VERSION 5.7 ;
  NOWIREEXTENSIONATPIN ON ;
  DIVIDERCHAR "/" ;
  BUSBITCHARS "[]" ;
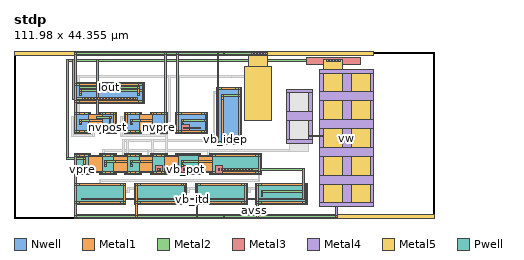
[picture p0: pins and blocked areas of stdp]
MACRO stdp
  CLASS BLOCK ;
  FOREIGN stdp ;
  ORIGIN 0.000 0.000 ;
  SIZE 111.980 BY 44.355 ;
  PIN avdd
    USE POWER ;
    PORT
      LAYER Nwell ;
        RECT 16.000 30.555 34.860 36.155 ;
        RECT 16.000 22.655 20.490 28.255 ;
        RECT 22.790 22.655 27.280 28.255 ;
        RECT 29.580 22.655 34.070 28.255 ;
        RECT 36.370 22.655 40.860 28.255 ;
        RECT 43.160 22.655 51.620 28.255 ;
        RECT 53.920 19.610 60.580 34.900 ;
      LAYER Metal1 ;
        RECT 16.230 43.605 16.730 44.105 ;
        RECT 40.170 43.605 40.670 44.105 ;
        RECT 43.390 43.605 43.890 44.105 ;
        RECT 54.150 43.605 54.650 44.105 ;
        RECT 16.230 35.945 16.690 43.605 ;
        RECT 16.230 35.445 16.730 35.945 ;
        RECT 17.580 35.445 33.280 35.945 ;
        RECT 34.130 35.445 34.630 35.945 ;
        RECT 16.230 31.265 16.690 35.445 ;
        RECT 34.170 34.250 34.630 35.445 ;
        RECT 17.400 33.750 17.900 34.250 ;
        RECT 34.130 33.750 34.630 34.250 ;
        RECT 17.420 33.200 17.880 33.750 ;
        RECT 17.400 32.700 17.900 33.200 ;
        RECT 34.170 31.265 34.630 33.750 ;
        RECT 16.230 30.765 16.730 31.265 ;
        RECT 17.580 30.765 33.280 31.265 ;
        RECT 34.130 30.765 34.630 31.265 ;
        RECT 16.230 28.045 16.690 30.765 ;
        RECT 40.170 28.045 40.630 43.605 ;
        RECT 16.230 27.545 16.730 28.045 ;
        RECT 17.595 27.545 18.895 28.045 ;
        RECT 19.760 27.615 20.260 28.045 ;
        RECT 23.020 27.615 23.520 28.045 ;
        RECT 19.760 27.545 23.520 27.615 ;
        RECT 24.385 27.545 25.685 28.045 ;
        RECT 26.550 27.545 27.050 28.045 ;
        RECT 16.230 23.365 16.690 27.545 ;
        RECT 19.800 26.350 23.480 27.545 ;
        RECT 17.400 25.850 17.900 26.350 ;
        RECT 19.760 25.850 23.480 26.350 ;
        RECT 17.420 25.300 17.880 25.850 ;
        RECT 17.400 24.800 17.900 25.300 ;
        RECT 19.800 23.365 23.480 25.850 ;
        RECT 26.590 23.365 27.050 27.545 ;
        RECT 16.230 22.865 16.730 23.365 ;
        RECT 17.595 22.865 18.895 23.365 ;
        RECT 19.760 23.295 23.520 23.365 ;
        RECT 19.760 22.865 20.260 23.295 ;
        RECT 23.020 22.865 23.520 23.295 ;
        RECT 24.385 22.865 25.685 23.365 ;
        RECT 26.550 22.865 27.050 23.365 ;
        RECT 29.810 27.545 30.310 28.045 ;
        RECT 31.175 27.545 32.475 28.045 ;
        RECT 33.340 27.615 33.840 28.045 ;
        RECT 36.600 27.615 37.100 28.045 ;
        RECT 33.340 27.545 37.100 27.615 ;
        RECT 37.965 27.545 39.265 28.045 ;
        RECT 40.130 27.545 40.630 28.045 ;
        RECT 29.810 23.365 30.270 27.545 ;
        RECT 33.380 26.350 37.060 27.545 ;
        RECT 30.980 25.850 31.480 26.350 ;
        RECT 33.340 25.850 37.060 26.350 ;
        RECT 31.000 25.300 31.460 25.850 ;
        RECT 30.980 24.800 31.480 25.300 ;
        RECT 33.380 23.365 37.060 25.850 ;
        RECT 40.170 23.365 40.630 27.545 ;
        RECT 29.810 22.865 30.310 23.365 ;
        RECT 31.175 22.865 32.475 23.365 ;
        RECT 33.340 23.295 37.100 23.365 ;
        RECT 33.340 22.865 33.840 23.295 ;
        RECT 36.600 22.865 37.100 23.295 ;
        RECT 37.965 22.865 39.265 23.365 ;
        RECT 40.130 22.865 40.630 23.365 ;
        RECT 43.390 28.045 43.850 43.605 ;
        RECT 54.150 34.690 54.610 43.605 ;
        RECT 54.150 34.190 54.650 34.690 ;
        RECT 55.400 34.190 59.100 34.690 ;
        RECT 59.850 34.190 60.350 34.690 ;
        RECT 43.390 27.545 43.890 28.045 ;
        RECT 44.740 27.545 50.040 28.045 ;
        RECT 50.890 27.545 51.390 28.045 ;
        RECT 43.390 23.365 43.850 27.545 ;
        RECT 50.930 26.350 51.390 27.545 ;
        RECT 44.560 25.850 45.060 26.350 ;
        RECT 50.890 25.850 51.390 26.350 ;
        RECT 44.580 25.300 45.040 25.850 ;
        RECT 44.560 24.800 45.060 25.300 ;
        RECT 50.930 23.365 51.390 25.850 ;
        RECT 43.390 22.865 43.890 23.365 ;
        RECT 44.740 22.865 50.040 23.365 ;
        RECT 50.890 22.865 51.390 23.365 ;
        RECT 54.150 20.320 54.610 34.190 ;
        RECT 59.890 33.000 60.350 34.190 ;
        RECT 55.320 32.500 55.820 33.000 ;
        RECT 59.850 32.500 60.350 33.000 ;
        RECT 55.340 31.500 55.800 32.500 ;
        RECT 55.320 22.200 55.820 31.500 ;
        RECT 55.340 21.750 55.800 22.200 ;
        RECT 59.890 20.320 60.350 32.500 ;
        RECT 54.150 19.820 54.650 20.320 ;
        RECT 55.400 19.820 59.100 20.320 ;
        RECT 59.850 19.820 60.350 20.320 ;
      LAYER Metal2 ;
        RECT 16.230 43.605 67.580 44.105 ;
        RECT 16.230 35.445 34.630 35.945 ;
        RECT 17.400 33.750 34.630 34.250 ;
        RECT 54.150 34.190 60.350 34.690 ;
        RECT 17.400 32.700 17.900 33.200 ;
        RECT 55.320 32.500 60.350 33.000 ;
        RECT 16.230 30.765 34.630 31.265 ;
        RECT 16.230 27.545 20.260 28.045 ;
        RECT 23.020 27.545 27.050 28.045 ;
        RECT 29.810 27.545 33.840 28.045 ;
        RECT 36.600 27.545 40.630 28.045 ;
        RECT 43.390 27.545 51.390 28.045 ;
        RECT 17.400 25.850 20.260 26.350 ;
        RECT 30.980 25.850 33.840 26.350 ;
        RECT 44.560 25.850 51.390 26.350 ;
        RECT 17.400 24.800 17.900 25.300 ;
        RECT 30.980 24.800 31.480 25.300 ;
        RECT 44.560 24.800 45.060 25.300 ;
        RECT 16.230 22.865 20.260 23.365 ;
        RECT 23.020 22.865 27.050 23.365 ;
        RECT 29.810 22.865 33.840 23.365 ;
        RECT 36.600 22.865 40.630 23.365 ;
        RECT 43.390 22.865 51.390 23.365 ;
        RECT 55.320 21.750 55.820 31.950 ;
        RECT 54.150 19.820 60.350 20.320 ;
      LAYER Metal3 ;
        RECT 55.740 43.605 56.240 44.105 ;
        RECT 63.230 43.605 63.730 44.105 ;
        RECT 64.030 43.605 64.530 44.105 ;
        RECT 64.830 43.605 65.330 44.105 ;
        RECT 65.630 43.605 66.130 44.105 ;
        RECT 66.430 43.605 66.930 44.105 ;
      LAYER Metal4 ;
        RECT 55.740 43.605 56.240 44.105 ;
        RECT 63.230 43.605 63.730 44.105 ;
        RECT 64.030 43.605 64.530 44.105 ;
        RECT 64.830 43.605 65.330 44.105 ;
        RECT 65.630 43.605 66.130 44.105 ;
        RECT 66.430 43.605 66.930 44.105 ;
      LAYER Metal5 ;
        RECT 0.000 43.355 95.980 44.355 ;
        RECT 62.580 40.355 67.580 43.355 ;
        RECT 61.580 25.955 68.580 40.355 ;
    END
  END avdd
  PIN avss
    USE GROUND ;
    PORT
      LAYER Pwell ;
        RECT 16.000 11.600 20.490 17.200 ;
        RECT 22.790 11.600 27.280 17.200 ;
        RECT 29.580 11.600 34.070 17.200 ;
        RECT 36.370 11.600 40.860 17.200 ;
        RECT 43.160 11.545 49.820 17.255 ;
        RECT 52.120 11.600 65.980 17.200 ;
        RECT 16.000 3.700 29.860 9.300 ;
        RECT 32.160 3.700 46.020 9.300 ;
        RECT 48.320 3.700 62.180 9.300 ;
        RECT 64.480 3.700 78.340 9.300 ;
      LAYER Metal1 ;
        RECT 16.230 16.490 16.730 16.990 ;
        RECT 17.595 16.490 18.895 16.990 ;
        RECT 19.760 16.560 20.260 16.990 ;
        RECT 23.020 16.560 23.520 16.990 ;
        RECT 19.760 16.490 23.520 16.560 ;
        RECT 24.385 16.490 25.685 16.990 ;
        RECT 26.550 16.560 27.050 16.990 ;
        RECT 29.810 16.560 30.310 16.990 ;
        RECT 26.550 16.490 30.310 16.560 ;
        RECT 31.175 16.490 32.475 16.990 ;
        RECT 33.340 16.560 33.840 16.990 ;
        RECT 36.600 16.560 37.100 16.990 ;
        RECT 33.340 16.490 37.100 16.560 ;
        RECT 37.965 16.490 39.265 16.990 ;
        RECT 40.130 16.560 40.630 16.990 ;
        RECT 43.390 16.560 43.890 17.045 ;
        RECT 40.130 16.545 43.890 16.560 ;
        RECT 44.640 16.545 48.340 17.045 ;
        RECT 49.090 16.615 49.590 17.045 ;
        RECT 52.350 16.615 52.850 16.990 ;
        RECT 49.090 16.545 52.850 16.615 ;
        RECT 40.130 16.490 43.850 16.545 ;
        RECT 16.230 12.310 16.690 16.490 ;
        RECT 19.800 12.310 23.480 16.490 ;
        RECT 26.590 15.295 30.270 16.490 ;
        RECT 33.380 15.295 37.060 16.490 ;
        RECT 24.190 14.795 24.690 15.295 ;
        RECT 26.550 14.795 30.270 15.295 ;
        RECT 30.980 14.795 31.480 15.295 ;
        RECT 33.340 14.795 37.060 15.295 ;
        RECT 24.210 14.245 24.670 14.795 ;
        RECT 24.190 13.745 24.690 14.245 ;
        RECT 26.590 12.310 30.270 14.795 ;
        RECT 31.000 14.245 31.460 14.795 ;
        RECT 30.980 13.745 31.480 14.245 ;
        RECT 33.380 12.310 37.060 14.795 ;
        RECT 40.170 12.310 43.850 16.490 ;
        RECT 49.130 16.490 52.850 16.545 ;
        RECT 53.600 16.490 64.500 16.990 ;
        RECT 65.250 16.490 65.750 16.990 ;
        RECT 49.130 15.355 52.810 16.490 ;
        RECT 44.560 14.855 45.060 15.355 ;
        RECT 49.090 14.855 52.810 15.355 ;
        RECT 44.580 14.250 45.040 14.855 ;
        RECT 44.560 13.750 45.060 14.250 ;
        RECT 44.580 13.695 45.040 13.750 ;
        RECT 16.230 11.810 16.730 12.310 ;
        RECT 17.595 11.810 18.895 12.310 ;
        RECT 19.760 12.240 23.520 12.310 ;
        RECT 19.760 11.810 20.260 12.240 ;
        RECT 23.020 11.810 23.520 12.240 ;
        RECT 24.385 11.810 25.685 12.310 ;
        RECT 26.550 12.240 30.310 12.310 ;
        RECT 26.550 11.810 27.050 12.240 ;
        RECT 29.810 11.810 30.310 12.240 ;
        RECT 31.175 11.810 32.475 12.310 ;
        RECT 33.340 12.240 37.100 12.310 ;
        RECT 33.340 11.810 33.840 12.240 ;
        RECT 36.600 11.810 37.100 12.240 ;
        RECT 37.965 11.810 39.265 12.310 ;
        RECT 40.130 12.255 43.850 12.310 ;
        RECT 49.130 12.310 52.810 14.855 ;
        RECT 65.290 12.310 65.750 16.490 ;
        RECT 49.130 12.255 52.850 12.310 ;
        RECT 40.130 12.240 43.890 12.255 ;
        RECT 40.130 11.810 40.630 12.240 ;
        RECT 16.230 9.090 16.690 11.810 ;
        RECT 43.390 11.755 43.890 12.240 ;
        RECT 44.640 11.755 48.340 12.255 ;
        RECT 49.090 12.185 52.850 12.255 ;
        RECT 49.090 11.755 49.590 12.185 ;
        RECT 52.350 11.810 52.850 12.185 ;
        RECT 53.600 11.810 64.500 12.310 ;
        RECT 65.250 11.810 65.750 12.310 ;
        RECT 16.230 8.590 16.730 9.090 ;
        RECT 17.480 8.590 28.380 9.090 ;
        RECT 29.130 8.590 29.630 9.090 ;
        RECT 16.230 4.410 16.690 8.590 ;
        RECT 29.170 4.410 29.630 8.590 ;
        RECT 16.230 3.910 16.730 4.410 ;
        RECT 17.480 3.910 28.380 4.410 ;
        RECT 29.130 3.910 29.630 4.410 ;
        RECT 32.390 8.590 32.890 9.090 ;
        RECT 33.640 8.590 44.540 9.090 ;
        RECT 45.290 8.590 45.790 9.090 ;
        RECT 32.390 4.410 32.850 8.590 ;
        RECT 45.330 4.410 45.790 8.590 ;
        RECT 32.390 3.910 32.890 4.410 ;
        RECT 33.640 3.910 44.540 4.410 ;
        RECT 45.290 3.910 45.790 4.410 ;
        RECT 48.550 8.590 49.050 9.090 ;
        RECT 49.800 8.590 60.700 9.090 ;
        RECT 61.450 8.590 61.950 9.090 ;
        RECT 48.550 4.410 49.010 8.590 ;
        RECT 61.490 4.410 61.950 8.590 ;
        RECT 48.550 3.910 49.050 4.410 ;
        RECT 49.800 3.910 60.700 4.410 ;
        RECT 61.450 3.910 61.950 4.410 ;
        RECT 64.710 8.590 65.210 9.090 ;
        RECT 65.960 8.590 76.860 9.090 ;
        RECT 77.610 8.590 78.110 9.090 ;
        RECT 64.710 4.410 65.170 8.590 ;
        RECT 77.650 7.395 78.110 8.590 ;
        RECT 65.880 6.895 66.380 7.395 ;
        RECT 77.610 6.895 78.110 7.395 ;
        RECT 65.900 6.345 66.360 6.895 ;
        RECT 65.880 5.845 66.380 6.345 ;
        RECT 77.650 4.410 78.110 6.895 ;
        RECT 64.710 3.910 65.210 4.410 ;
        RECT 65.960 3.910 76.860 4.410 ;
        RECT 77.610 3.910 78.110 4.410 ;
        RECT 16.230 0.750 16.690 3.910 ;
        RECT 32.390 0.750 32.850 3.910 ;
        RECT 48.550 0.750 49.010 3.910 ;
        RECT 64.710 0.750 65.170 3.910 ;
        RECT 16.230 0.250 16.730 0.750 ;
        RECT 32.390 0.250 32.890 0.750 ;
        RECT 48.550 0.250 49.050 0.750 ;
        RECT 64.670 0.250 65.170 0.750 ;
      LAYER Metal2 ;
        RECT 16.230 16.490 20.260 16.990 ;
        RECT 23.020 16.490 27.050 16.990 ;
        RECT 29.810 16.490 33.840 16.990 ;
        RECT 36.600 16.490 40.630 16.990 ;
        RECT 43.390 16.545 49.590 17.045 ;
        RECT 52.350 16.490 65.750 16.990 ;
        RECT 24.190 14.795 27.050 15.295 ;
        RECT 30.980 14.795 33.840 15.295 ;
        RECT 44.560 14.855 49.590 15.355 ;
        RECT 24.190 13.745 24.690 14.245 ;
        RECT 30.980 13.745 31.480 14.245 ;
        RECT 44.560 13.695 45.060 14.305 ;
        RECT 16.230 11.810 20.260 12.310 ;
        RECT 23.020 11.810 27.050 12.310 ;
        RECT 29.810 11.810 33.840 12.310 ;
        RECT 36.600 11.810 40.630 12.310 ;
        RECT 43.390 11.755 49.590 12.255 ;
        RECT 52.350 11.810 65.750 12.310 ;
        RECT 16.230 8.590 29.630 9.090 ;
        RECT 32.390 8.590 45.790 9.090 ;
        RECT 48.550 8.590 61.950 9.090 ;
        RECT 64.710 8.590 78.110 9.090 ;
        RECT 65.880 6.895 78.110 7.395 ;
        RECT 65.880 5.845 66.380 6.345 ;
        RECT 16.230 3.910 29.630 4.410 ;
        RECT 32.390 3.910 45.790 4.410 ;
        RECT 48.550 3.910 61.950 4.410 ;
        RECT 64.710 3.910 78.110 4.410 ;
        RECT 16.230 0.250 86.130 0.750 ;
      LAYER Metal3 ;
        RECT 55.740 0.250 56.240 0.750 ;
        RECT 85.630 0.250 86.130 0.750 ;
      LAYER Metal4 ;
        RECT 81.580 38.600 95.980 39.600 ;
        RECT 72.580 33.355 79.580 34.355 ;
        RECT 72.580 28.355 73.580 33.355 ;
        RECT 78.580 28.355 79.580 33.355 ;
        RECT 72.580 25.955 79.580 28.355 ;
        RECT 72.580 20.955 73.580 25.955 ;
        RECT 78.580 22.105 79.580 25.955 ;
        RECT 81.580 33.600 82.580 38.600 ;
        RECT 87.580 33.600 89.980 38.600 ;
        RECT 94.980 33.600 95.980 38.600 ;
        RECT 81.580 31.200 95.980 33.600 ;
        RECT 81.580 26.200 82.580 31.200 ;
        RECT 87.580 26.200 89.980 31.200 ;
        RECT 94.980 26.200 95.980 31.200 ;
        RECT 81.580 23.800 95.980 26.200 ;
        RECT 81.580 22.105 82.580 23.800 ;
        RECT 78.580 21.605 82.580 22.105 ;
        RECT 78.580 20.955 79.580 21.605 ;
        RECT 72.580 19.955 79.580 20.955 ;
        RECT 81.580 18.800 82.580 21.605 ;
        RECT 87.580 18.800 89.980 23.800 ;
        RECT 94.980 18.800 95.980 23.800 ;
        RECT 81.580 16.400 95.980 18.800 ;
        RECT 81.580 11.400 82.580 16.400 ;
        RECT 87.580 11.400 89.980 16.400 ;
        RECT 94.980 11.400 95.980 16.400 ;
        RECT 81.580 9.000 95.980 11.400 ;
        RECT 81.580 4.000 82.580 9.000 ;
        RECT 87.580 4.000 89.980 9.000 ;
        RECT 94.980 4.000 95.980 9.000 ;
        RECT 81.580 3.000 95.980 4.000 ;
        RECT 55.740 0.250 56.240 0.750 ;
        RECT 85.630 0.250 86.130 3.000 ;
      LAYER Metal5 ;
        RECT 16.000 0.000 111.980 1.000 ;
    END
  END avss
  PIN nvpost
    ANTENNAGATEAREA 0.315000 ;
    PORT
      LAYER Metal1 ;
        RECT 24.785 23.760 25.285 24.260 ;
      LAYER Metal2 ;
        RECT 24.720 23.760 25.350 24.260 ;
      LAYER Metal3 ;
        RECT 24.035 23.010 26.035 25.010 ;
    END
  END nvpost
  PIN vpost
    ANTENNAGATEAREA 0.315000 ;
    PORT
      LAYER Metal1 ;
        RECT 38.365 12.705 38.865 13.205 ;
      LAYER Metal2 ;
        RECT 38.300 12.705 38.930 13.205 ;
      LAYER Metal3 ;
        RECT 37.615 11.955 39.615 13.955 ;
    END
  END vpost
  PIN vpre
    ANTENNAGATEAREA 0.315000 ;
    PORT
      LAYER Metal1 ;
        RECT 17.995 12.705 18.495 13.205 ;
      LAYER Metal2 ;
        RECT 17.930 12.705 18.560 13.205 ;
      LAYER Metal3 ;
        RECT 17.245 11.955 19.245 13.955 ;
    END
  END vpre
  PIN vb_idep
    ANTENNAGATEAREA 28.559999 ;
    PORT
      LAYER Metal1 ;
        RECT 56.200 20.710 56.700 21.210 ;
        RECT 57.000 20.710 57.500 21.210 ;
        RECT 57.800 20.710 58.300 21.210 ;
      LAYER Metal2 ;
        RECT 55.850 20.710 58.650 21.210 ;
      LAYER Metal3 ;
        RECT 55.450 19.960 57.450 21.960 ;
    END
  END vb_idep
  PIN vb_itd
    ANTENNAGATEAREA 25.000000 ;
    PORT
      LAYER Metal1 ;
        RECT 54.400 12.705 54.900 13.205 ;
        RECT 55.200 12.705 55.700 13.205 ;
        RECT 56.000 12.705 56.500 13.205 ;
        RECT 56.800 12.705 57.300 13.205 ;
        RECT 57.600 12.705 58.100 13.205 ;
        RECT 58.400 12.705 58.900 13.205 ;
        RECT 59.200 12.705 59.700 13.205 ;
        RECT 60.000 12.705 60.500 13.205 ;
        RECT 60.800 12.705 61.300 13.205 ;
        RECT 61.600 12.705 62.100 13.205 ;
        RECT 62.400 12.705 62.900 13.205 ;
        RECT 63.200 12.705 63.700 13.205 ;
        RECT 18.280 4.805 18.780 5.305 ;
        RECT 19.080 4.805 19.580 5.305 ;
        RECT 19.880 4.805 20.380 5.305 ;
        RECT 20.680 4.805 21.180 5.305 ;
        RECT 21.480 4.805 21.980 5.305 ;
        RECT 22.280 4.805 22.780 5.305 ;
        RECT 23.080 4.805 23.580 5.305 ;
        RECT 23.880 4.805 24.380 5.305 ;
        RECT 24.680 4.805 25.180 5.305 ;
        RECT 25.480 4.805 25.980 5.305 ;
        RECT 26.280 4.805 26.780 5.305 ;
        RECT 27.080 4.805 27.580 5.305 ;
        RECT 34.440 4.805 34.940 5.305 ;
        RECT 35.240 4.805 35.740 5.305 ;
        RECT 36.040 4.805 36.540 5.305 ;
        RECT 36.840 4.805 37.340 5.305 ;
        RECT 37.640 4.805 38.140 5.305 ;
        RECT 38.440 4.805 38.940 5.305 ;
        RECT 39.240 4.805 39.740 5.305 ;
        RECT 40.040 4.805 40.540 5.305 ;
        RECT 40.840 4.805 41.340 5.305 ;
        RECT 41.640 4.805 42.140 5.305 ;
        RECT 42.440 4.805 42.940 5.305 ;
        RECT 43.240 4.805 43.740 5.305 ;
        RECT 50.600 4.805 51.100 5.305 ;
        RECT 51.400 4.805 51.900 5.305 ;
        RECT 52.200 4.805 52.700 5.305 ;
        RECT 53.000 4.805 53.500 5.305 ;
        RECT 53.800 4.805 54.300 5.305 ;
        RECT 54.600 4.805 55.100 5.305 ;
        RECT 55.400 4.805 55.900 5.305 ;
        RECT 56.200 4.805 56.700 5.305 ;
        RECT 57.000 4.805 57.500 5.305 ;
        RECT 57.800 4.805 58.300 5.305 ;
        RECT 58.600 4.805 59.100 5.305 ;
        RECT 59.400 4.805 59.900 5.305 ;
        RECT 66.760 4.805 67.260 5.305 ;
        RECT 67.560 4.805 68.060 5.305 ;
        RECT 68.360 4.805 68.860 5.305 ;
        RECT 69.160 4.805 69.660 5.305 ;
        RECT 69.960 4.805 70.460 5.305 ;
        RECT 70.760 4.805 71.260 5.305 ;
        RECT 71.560 4.805 72.060 5.305 ;
        RECT 72.360 4.805 72.860 5.305 ;
        RECT 73.160 4.805 73.660 5.305 ;
        RECT 73.960 4.805 74.460 5.305 ;
        RECT 74.760 4.805 75.260 5.305 ;
        RECT 75.560 4.805 76.060 5.305 ;
      LAYER Metal2 ;
        RECT 54.050 12.705 77.410 13.205 ;
        RECT 17.930 4.805 77.410 5.305 ;
      LAYER Metal3 ;
        RECT 53.650 11.955 55.650 13.955 ;
        RECT 76.910 4.805 77.410 13.205 ;
    END
  END vb_itd
  PIN vb_itp
    ANTENNAGATEAREA 2.300000 ;
    PORT
      LAYER Metal1 ;
        RECT 45.540 23.760 46.040 24.260 ;
        RECT 46.340 23.760 46.840 24.260 ;
        RECT 47.140 23.760 47.640 24.260 ;
        RECT 47.940 23.760 48.440 24.260 ;
        RECT 48.740 23.760 49.240 24.260 ;
      LAYER Metal2 ;
        RECT 45.090 23.760 49.690 24.260 ;
      LAYER Metal3 ;
        RECT 44.790 23.010 46.790 25.010 ;
    END
  END vb_itp
  PIN vb_pot
    ANTENNAGATEAREA 1.708000 ;
    PORT
      LAYER Metal1 ;
        RECT 45.440 12.650 45.940 13.150 ;
        RECT 46.240 12.650 46.740 13.150 ;
        RECT 47.040 12.650 47.540 13.150 ;
      LAYER Metal2 ;
        RECT 45.090 12.650 47.890 13.150 ;
      LAYER Metal3 ;
        RECT 44.690 11.900 46.690 13.900 ;
    END
  END vb_pot
  PIN nvpre
    ANTENNAGATEAREA 0.315000 ;
    PORT
      LAYER Metal1 ;
        RECT 38.365 23.760 38.865 24.260 ;
      LAYER Metal2 ;
        RECT 38.300 23.760 38.930 24.260 ;
      LAYER Metal3 ;
        RECT 37.615 23.010 39.615 25.010 ;
      LAYER Metal4 ;
        RECT 38.365 23.760 38.865 24.260 ;
    END
  END nvpre
  PIN Iout
    ANTENNADIFFAREA 0.300000 ;
    PORT
      LAYER Metal1 ;
        RECT 32.960 34.550 33.460 35.050 ;
        RECT 32.980 33.200 33.440 34.550 ;
        RECT 32.960 32.700 33.460 33.200 ;
      LAYER Metal2 ;
        RECT 17.400 34.550 33.460 35.050 ;
        RECT 32.960 32.700 33.460 33.200 ;
      LAYER Metal3 ;
        RECT 24.430 33.800 26.430 35.800 ;
    END
  END Iout
  PIN vw
    ANTENNAGATEAREA 7.500000 ;
    ANTENNADIFFAREA 0.600000 ;
    PORT
      LAYER Metal1 ;
        RECT 18.380 31.660 18.880 32.160 ;
        RECT 19.180 31.660 19.680 32.160 ;
        RECT 19.980 31.660 20.480 32.160 ;
        RECT 20.780 31.660 21.280 32.160 ;
        RECT 21.580 31.660 22.080 32.160 ;
        RECT 22.380 31.660 22.880 32.160 ;
        RECT 23.180 31.660 23.680 32.160 ;
        RECT 23.980 31.660 24.480 32.160 ;
        RECT 24.780 31.660 25.280 32.160 ;
        RECT 25.580 31.660 26.080 32.160 ;
        RECT 26.380 31.660 26.880 32.160 ;
        RECT 27.180 31.660 27.680 32.160 ;
        RECT 27.980 31.660 28.480 32.160 ;
        RECT 28.780 31.660 29.280 32.160 ;
        RECT 29.580 31.660 30.080 32.160 ;
        RECT 30.380 31.660 30.880 32.160 ;
        RECT 31.180 31.660 31.680 32.160 ;
        RECT 31.980 31.660 32.480 32.160 ;
        RECT 25.380 26.650 25.880 27.150 ;
        RECT 25.400 25.300 25.860 26.650 ;
        RECT 25.380 24.800 25.880 25.300 ;
        RECT 18.590 15.595 19.090 16.095 ;
        RECT 18.610 14.245 19.070 15.595 ;
        RECT 18.590 13.745 19.090 14.245 ;
      LAYER Metal2 ;
        RECT 13.900 41.650 87.580 42.150 ;
        RECT 15.630 31.660 32.930 32.160 ;
        RECT 21.940 26.650 25.880 27.150 ;
        RECT 25.380 24.800 25.880 25.300 ;
        RECT 13.900 15.595 19.090 16.095 ;
        RECT 18.590 13.745 19.090 14.245 ;
      LAYER Metal3 ;
        RECT 13.900 15.595 14.400 42.150 ;
        RECT 15.630 31.660 16.130 42.150 ;
        RECT 21.940 26.650 22.440 42.150 ;
        RECT 77.880 40.900 92.280 42.900 ;
      LAYER Metal4 ;
        RECT 83.230 41.650 83.730 42.150 ;
        RECT 84.030 41.650 84.530 42.150 ;
        RECT 84.830 41.650 85.330 42.150 ;
        RECT 85.630 41.650 86.130 42.150 ;
        RECT 86.430 41.650 86.930 42.150 ;
      LAYER Metal5 ;
        RECT 82.580 39.600 87.580 42.150 ;
        RECT 81.580 3.000 95.980 39.600 ;
    END
  END vw
  OBS
      LAYER Metal1 ;
        RECT 58.680 33.300 59.180 33.800 ;
        RECT 58.700 31.500 59.160 33.300 ;
        RECT 18.590 26.650 19.090 27.150 ;
        RECT 32.170 26.650 32.670 27.150 ;
        RECT 38.960 26.650 39.460 27.150 ;
        RECT 49.720 26.650 50.220 27.150 ;
        RECT 18.610 25.300 19.070 26.650 ;
        RECT 24.190 25.850 24.690 26.350 ;
        RECT 24.210 25.300 24.670 25.850 ;
        RECT 32.190 25.300 32.650 26.650 ;
        RECT 37.770 25.850 38.270 26.350 ;
        RECT 37.790 25.300 38.250 25.850 ;
        RECT 38.980 25.300 39.440 26.650 ;
        RECT 49.740 25.300 50.200 26.650 ;
        RECT 18.590 24.800 19.090 25.300 ;
        RECT 24.190 24.800 24.690 25.300 ;
        RECT 32.170 24.800 32.670 25.300 ;
        RECT 37.770 24.800 38.270 25.300 ;
        RECT 38.960 24.800 39.460 25.300 ;
        RECT 49.720 24.800 50.220 25.300 ;
        RECT 17.995 23.760 18.495 24.260 ;
        RECT 31.575 23.760 32.075 24.260 ;
        RECT 58.680 22.200 59.180 31.500 ;
        RECT 58.700 21.750 59.160 22.200 ;
        RECT 25.380 15.595 25.880 16.095 ;
        RECT 32.170 15.595 32.670 16.095 ;
        RECT 38.960 15.595 39.460 16.095 ;
        RECT 47.920 15.655 48.420 16.155 ;
        RECT 17.400 14.795 17.900 15.295 ;
        RECT 17.420 14.245 17.880 14.795 ;
        RECT 25.400 14.245 25.860 15.595 ;
        RECT 32.190 14.245 32.650 15.595 ;
        RECT 37.770 14.795 38.270 15.295 ;
        RECT 37.790 14.245 38.250 14.795 ;
        RECT 38.980 14.245 39.440 15.595 ;
        RECT 47.940 14.250 48.400 15.655 ;
        RECT 64.080 15.595 64.580 16.095 ;
        RECT 53.520 14.795 54.020 15.295 ;
        RECT 17.400 13.745 17.900 14.245 ;
        RECT 25.380 13.745 25.880 14.245 ;
        RECT 32.170 13.745 32.670 14.245 ;
        RECT 37.770 13.745 38.270 14.245 ;
        RECT 38.960 13.745 39.460 14.245 ;
        RECT 47.920 13.750 48.420 14.250 ;
        RECT 53.540 14.245 54.000 14.795 ;
        RECT 64.100 14.245 64.560 15.595 ;
        RECT 47.940 13.695 48.400 13.750 ;
        RECT 53.520 13.745 54.020 14.245 ;
        RECT 64.080 13.745 64.580 14.245 ;
        RECT 24.785 12.705 25.285 13.205 ;
        RECT 31.575 12.705 32.075 13.205 ;
        RECT 27.960 7.695 28.460 8.195 ;
        RECT 44.120 7.695 44.620 8.195 ;
        RECT 60.280 7.695 60.780 8.195 ;
        RECT 76.440 7.695 76.940 8.195 ;
        RECT 17.400 6.895 17.900 7.395 ;
        RECT 17.420 6.345 17.880 6.895 ;
        RECT 27.980 6.345 28.440 7.695 ;
        RECT 33.560 6.895 34.060 7.395 ;
        RECT 33.580 6.345 34.040 6.895 ;
        RECT 44.140 6.345 44.600 7.695 ;
        RECT 49.720 6.895 50.220 7.395 ;
        RECT 49.740 6.345 50.200 6.895 ;
        RECT 60.300 6.345 60.760 7.695 ;
        RECT 76.460 6.345 76.920 7.695 ;
        RECT 17.400 5.845 17.900 6.345 ;
        RECT 27.960 5.845 28.460 6.345 ;
        RECT 33.560 5.845 34.060 6.345 ;
        RECT 44.120 5.845 44.620 6.345 ;
        RECT 49.720 5.845 50.220 6.345 ;
        RECT 60.280 5.845 60.780 6.345 ;
        RECT 76.440 5.845 76.940 6.345 ;
      LAYER Metal2 ;
        RECT 16.930 37.405 58.480 37.905 ;
        RECT 53.070 33.300 59.180 33.800 ;
        RECT 15.400 26.650 19.090 27.150 ;
        RECT 28.480 26.650 32.670 27.150 ;
        RECT 34.690 26.650 39.460 27.150 ;
        RECT 43.560 26.650 50.220 27.150 ;
        RECT 20.840 25.850 25.880 26.350 ;
        RECT 37.770 25.850 41.710 26.350 ;
        RECT 18.590 24.800 19.090 25.300 ;
        RECT 24.190 24.800 24.690 25.300 ;
        RECT 32.170 24.800 32.670 25.300 ;
        RECT 37.770 24.800 38.270 25.300 ;
        RECT 38.960 24.800 39.460 25.300 ;
        RECT 49.720 24.800 50.220 25.300 ;
        RECT 16.930 23.760 18.560 24.260 ;
        RECT 31.510 23.760 35.190 24.260 ;
        RECT 15.400 21.650 21.340 22.150 ;
        RECT 28.480 21.650 40.920 22.150 ;
        RECT 58.680 21.750 59.180 31.950 ;
        RECT 29.010 20.300 53.570 20.800 ;
        RECT 23.720 17.645 78.580 18.145 ;
        RECT 20.840 15.595 25.880 16.095 ;
        RECT 29.980 15.595 32.670 16.095 ;
        RECT 36.770 15.595 39.460 16.095 ;
        RECT 40.420 15.655 48.420 16.155 ;
        RECT 51.520 15.595 64.580 16.095 ;
        RECT 17.400 14.795 21.340 15.295 ;
        RECT 35.470 14.795 39.460 15.295 ;
        RECT 53.520 14.795 65.580 15.295 ;
        RECT 17.400 13.745 17.900 14.245 ;
        RECT 25.380 13.745 25.880 14.245 ;
        RECT 32.170 13.745 32.670 14.245 ;
        RECT 37.770 13.745 38.270 14.245 ;
        RECT 38.960 13.745 39.460 14.245 ;
        RECT 47.920 13.695 48.420 14.305 ;
        RECT 53.520 13.745 54.020 14.245 ;
        RECT 64.080 13.745 64.580 14.245 ;
        RECT 23.720 12.705 25.350 13.205 ;
        RECT 29.010 12.705 32.140 13.205 ;
        RECT 22.680 9.745 65.580 10.245 ;
        RECT 17.400 7.695 28.460 8.195 ;
        RECT 30.210 7.695 44.620 8.195 ;
        RECT 46.370 7.695 60.780 8.195 ;
        RECT 62.530 7.695 76.940 8.195 ;
        RECT 17.400 6.895 30.710 7.395 ;
        RECT 33.560 6.895 46.870 7.395 ;
        RECT 49.720 6.895 63.030 7.395 ;
        RECT 17.400 5.845 17.900 6.345 ;
        RECT 27.960 5.845 28.460 6.345 ;
        RECT 33.560 5.845 34.060 6.345 ;
        RECT 44.120 5.845 44.620 6.345 ;
        RECT 49.720 5.845 50.220 6.345 ;
        RECT 60.280 5.845 60.780 6.345 ;
        RECT 76.440 5.845 76.940 6.345 ;
      LAYER Metal3 ;
        RECT 15.400 21.650 15.900 27.150 ;
        RECT 16.930 23.760 17.430 37.905 ;
        RECT 20.840 21.650 21.340 26.350 ;
        RECT 28.480 21.650 28.980 27.150 ;
        RECT 34.690 23.760 35.190 27.150 ;
        RECT 41.210 25.850 41.710 37.905 ;
        RECT 43.560 26.650 44.060 37.905 ;
        RECT 57.980 37.405 58.480 37.905 ;
        RECT 20.840 14.795 21.340 16.095 ;
        RECT 23.720 12.705 24.220 18.145 ;
        RECT 29.010 12.705 29.510 20.800 ;
        RECT 29.980 15.595 30.480 20.800 ;
        RECT 35.470 14.795 35.970 18.145 ;
        RECT 36.770 15.595 37.270 20.800 ;
        RECT 40.420 15.655 40.920 22.150 ;
        RECT 53.070 20.300 53.570 33.800 ;
        RECT 51.520 15.595 52.020 18.145 ;
        RECT 58.800 17.645 59.300 18.145 ;
        RECT 74.230 17.645 74.730 18.145 ;
        RECT 75.030 17.645 75.530 18.145 ;
        RECT 75.830 17.645 76.330 18.145 ;
        RECT 76.630 17.645 77.130 18.145 ;
        RECT 77.430 17.645 77.930 18.145 ;
        RECT 22.680 7.695 23.180 10.245 ;
        RECT 65.080 9.745 65.580 15.295 ;
        RECT 30.210 6.895 30.710 8.195 ;
        RECT 46.370 6.895 46.870 8.195 ;
        RECT 62.530 6.895 63.030 8.195 ;
      LAYER Metal4 ;
        RECT 61.580 39.355 68.580 40.355 ;
        RECT 61.580 37.905 62.580 39.355 ;
        RECT 57.980 37.405 62.580 37.905 ;
        RECT 61.580 34.355 62.580 37.405 ;
        RECT 67.580 34.355 68.580 39.355 ;
        RECT 61.580 31.955 68.580 34.355 ;
        RECT 61.580 26.955 62.580 31.955 ;
        RECT 67.580 26.955 68.580 31.955 ;
        RECT 61.580 25.955 68.580 26.955 ;
        RECT 74.230 17.645 74.730 18.145 ;
        RECT 75.030 17.645 75.530 18.145 ;
        RECT 75.830 17.645 76.330 18.145 ;
        RECT 76.630 17.645 77.130 18.145 ;
        RECT 77.430 17.645 77.930 18.145 ;
      LAYER Metal5 ;
        RECT 72.580 19.955 79.580 34.355 ;
        RECT 73.580 17.645 78.580 19.955 ;
  END
END stdp
END LIBRARY

